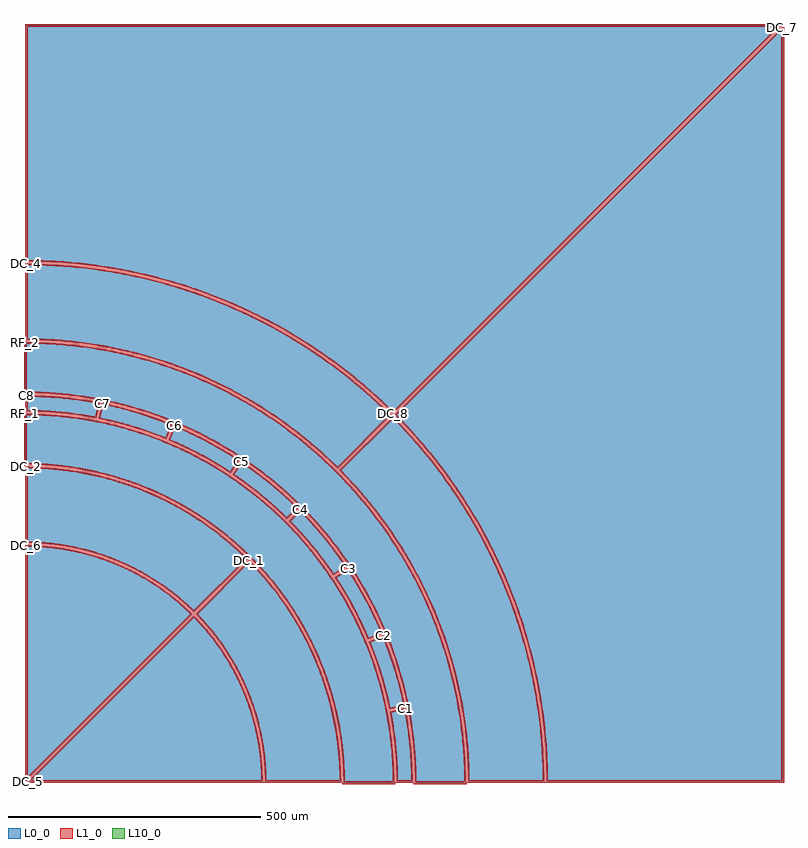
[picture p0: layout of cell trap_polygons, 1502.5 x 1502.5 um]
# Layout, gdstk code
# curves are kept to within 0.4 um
import gdstk
lib = gdstk.Library(unit=1e-6, precision=1e-09)
def P(c, l, *ps):  # polygons
    for p in ps: c.add(gdstk.Polygon(p, *l))
L0_0 = (0, 0)
L1_0 = (1, 0)
L10_0 = (10, 0)

trap_polygons = lib.new_cell('trap_polygons')
P(trap_polygons, L0_0, [(727.08,730.616),(691.717,764.181),(654.807,796.036),(609.899,830.945),(569.922,858.856),(528.671,884.846),(486.237,908.856),(442.715,930.833),(390.694,953.836),(345.151,971.245),(298.837,986.48),(251.854,999.508),(204.307,1010.299),(156.303,1018.83),(107.95,1025.082),(51.239,1029.476),(2.5,1030.747),(2.5,1497.5),(1493.964,1497.5)],
  [(1497.5,1493.964),(1497.5,2.5),(1030.747,2.5),(1029.476,51.239),(1025.082,107.95),(1018.83,156.303),(1010.299,204.307),(999.508,251.854),(986.48,298.837),(971.245,345.151),(953.836,390.694),(930.833,442.715),(908.856,486.237),(884.846,528.671),(858.856,569.922),(830.945,609.899),(796.036,654.807),(764.181,691.717),(730.616,727.08)],
  [(2.5,469.243),(28.188,468.403),(50.143,466.563),(71.986,463.695),(93.672,459.806),(115.15,454.902),(136.375,448.996),(160.754,440.856),(181.269,432.825),(201.385,423.839),(221.057,413.92),(240.241,403.088),(261.951,389.329),(279.936,376.605),(297.304,363.051),(314.017,348.696),(330.037,333.573),(2.5,6.036)],
  [(6.036,2.5),(333.573,330.037),(348.696,314.017),(363.051,297.304),(376.605,279.936),(389.329,261.951),(403.088,240.241),(413.92,221.057),(423.839,201.385),(432.825,181.269),(440.856,160.754),(448.996,136.375),(454.902,115.15),(459.806,93.672),(463.695,71.986),(466.563,50.143),(468.403,28.188),(469.243,2.5)],
  [(2.5,1025.747),(51.002,1024.481),(99.389,1020.924),(147.554,1015.082),(203.322,1005.397),(250.636,994.658),(305.121,979.318),(351.088,963.795),(396.27,946.115),(447.855,922.816),(490.991,900.606),(533.029,876.381),(573.874,850.195),(613.435,822.108),(651.623,792.181),(688.354,760.481),(723.545,727.08),(617.478,621.014),(582.322,654.095),(550.775,680.871),(517.998,706.128),(484.065,729.808),(449.051,751.858),(413.035,772.231),(376.096,790.879),(338.318,807.762),(299.785,822.841),(260.583,836.083),(220.798,847.459),(173.766,858.338),(133.028,865.587),(91.992,870.905),(43.864,874.651),(2.5,875.746)],
  [(727.08,723.545),(760.481,688.354),(792.181,651.623),(822.108,613.435),(850.195,573.874),(876.381,533.029),(900.606,490.991),(922.816,447.855),(946.115,396.27),(963.795,351.088),(979.318,305.121),(994.658,250.636),(1005.397,203.322),(1015.082,147.554),(1020.924,99.389),(1024.481,51.002),(1025.747,2.5),(875.746,2.5),(874.651,43.864),(870.905,91.992),(865.587,133.028),(858.338,173.766),(847.459,220.798),(836.083,260.583),(822.841,299.785),(807.762,338.318),(790.879,376.096),(772.231,413.035),(751.858,449.051),(729.808,484.065),(706.128,517.998),(680.871,550.775),(654.095,582.322),(621.014,617.478)],
  [(2.5,624.245),(31.897,623.435),(61.224,621.24),(90.414,617.668),(119.404,612.724),(148.129,606.42),(176.526,598.771),(209.155,588.169),(236.624,577.665),(263.568,565.88),(294.259,550.545),(319.861,536.075),(344.754,520.416),(368.881,503.602),(392.19,485.67),(418.28,463.39),(439.64,443.176),(333.573,337.108),(317.38,352.396),(297.607,369.247),(279.945,382.811),(261.665,395.53),(239.614,409.266),(220.137,420.063),(200.175,429.934),(179.772,438.857),(158.972,446.812),(137.822,453.782),(116.367,459.752),(94.657,464.708),(69.067,469.194),(46.965,471.919),(24.76,473.603),(2.5,474.243)],
  [(443.176,439.64),(463.39,418.28),(485.67,392.19),(503.602,368.881),(520.416,344.754),(536.075,319.861),(550.545,294.259),(565.88,263.568),(577.665,236.624),(588.169,209.155),(598.771,176.526),(606.42,148.129),(612.724,119.404),(617.668,90.414),(621.24,61.224),(623.435,31.897),(624.245,2.5),(474.243,2.5),(473.603,24.76),(471.919,46.965),(469.194,69.067),(464.708,94.657),(459.752,116.367),(453.782,137.822),(446.812,158.972),(438.857,179.772),(429.934,200.175),(420.063,220.137),(409.266,239.614),(395.53,261.665),(382.811,279.945),(369.247,297.607),(352.396,317.38),(337.108,333.573)],
  [(2.5,765.746),(38.822,764.765),(75.057,762.063),(111.122,757.644),(146.938,751.52),(140.792,720.625),(106.5,726.485),(71.969,730.714),(37.276,733.303),(2.5,734.246)],
  [(151.842,750.545),(187.274,742.497),(222.285,732.777),(256.796,721.408),(290.729,708.414),(278.674,679.311),(246.184,691.749),(213.142,702.633),(179.62,711.941),(145.696,719.65)],
  [(295.348,706.5),(328.53,691.694),(360.972,675.331),(392.601,657.447),(423.347,638.083),(405.846,611.892),(376.407,630.429),(346.123,647.551),(315.062,663.219),(283.293,677.398)],
  [(427.504,635.306),(457.16,614.311),(485.787,591.933),(513.319,568.222),(539.696,543.232),(517.422,520.958),(492.165,544.882),(465.803,567.583),(438.396,589.01),(410.004,609.114)],
  [(543.232,539.696),(568.222,513.319),(591.933,485.787),(614.311,457.16),(635.306,427.504),(609.114,410.004),(589.01,438.396),(567.583,465.803),(544.882,492.165),(520.958,517.422)],
  [(638.083,423.347),(657.447,392.601),(675.331,360.972),(691.694,328.53),(706.5,295.348),(677.398,283.293),(663.219,315.062),(647.551,346.123),(630.429,376.407),(611.892,405.846)],
  [(708.414,290.729),(721.408,256.796),(732.777,222.285),(742.497,187.274),(750.545,151.842),(719.65,145.696),(711.941,179.62),(702.633,213.142),(691.749,246.184),(679.311,278.674)],
  [(751.52,146.938),(757.644,111.122),(762.063,75.057),(764.765,38.822),(765.746,2.5),(734.246,2.5),(733.303,37.276),(730.714,71.969),(726.485,106.5),(720.625,140.792)],
  [(0,870.75),(41.018,869.783),(81.945,866.886),(129.457,861.073),(169.875,854.019),(209.916,845.069),(256.036,832.257),(294.956,819.272),(333.222,804.468),(370.747,787.878),(407.45,769.539),(449.121,745.987),(483.763,724.002),(517.331,700.41),(549.75,675.263),(586.026,644.034),(615.713,615.713),(644.034,586.026),(675.263,549.75),(700.41,517.331),(724.002,483.763),(745.987,449.121),(769.539,407.45),(787.878,370.747),(804.468,333.222),(819.272,294.956),(832.257,256.036),(845.069,209.916),(854.019,169.875),(861.073,129.457),(866.886,81.945),(869.783,41.018),(870.75,0),(770.75,0),(769.894,36.307),(766.736,78.558),(762.184,114.589),(755.94,150.366),(748.018,185.809),(738.435,220.839),(727.212,255.379),(712.08,294.953),(694.797,333.637),(678.309,365.996),(660.315,397.542),(640.855,428.206),(619.973,457.919),(593.873,491.295),(570.071,518.724),(545.003,545.003),(518.724,570.071),(491.295,593.873),(457.919,619.973),(428.206,640.855),(397.542,660.315),(365.996,678.309),(333.637,694.797),(294.953,712.08),(255.379,727.212),(220.839,738.435),(185.809,748.018),(150.366,755.94),(114.589,762.184),(78.558,766.736),(36.307,769.894),(0,770.75)],
  [(0,729.25),(34.352,728.44),(68.628,726.014),(102.752,721.975),(142.27,715.238),(175.804,707.742),(208.948,698.675),(247.025,686.137),(279.072,673.739),(310.5,659.845),(341.238,644.486),(376.137,624.761),(405.15,606.349),(433.263,586.591),(464.841,561.897),(490.794,539.376),(515.658,515.658),(539.376,490.794),(561.897,464.841),(586.591,433.263),(606.349,405.15),(624.761,376.137),(644.486,341.238),(659.845,310.5),(673.739,279.072),(686.137,247.025),(698.675,208.948),(707.742,175.804),(715.238,142.27),(721.975,102.752),(726.014,68.628),(728.44,34.352),(729.25,0),(629.25,0),(628.299,34.577),(625.973,64.136),(622.257,93.552),(617.159,122.761),(609.481,156.488),(601.433,185.025),(592.049,213.151),(581.351,240.804),(569.362,267.922),(556.11,294.445),(541.622,320.314),(523.202,349.593),(506.153,373.851),(487.981,397.279),(468.725,419.825),(444.947,444.947),(419.825,468.725),(397.279,487.981),(373.851,506.153),(349.593,523.202),(320.314,541.622),(294.445,556.11),(267.922,569.362),(240.804,581.351),(213.151,592.049),(185.025,601.433),(156.488,609.481),(122.761,617.159),(93.552,622.257),(64.136,625.973),(34.577,628.299),(0,629.25)])
P(trap_polygons, L1_0, [(404.701,950.689),(353.654,970.842),(307.349,986.48),(260.356,999.91),(212.781,1011.103),(164.73,1020.034),(108.211,1027.568),(59.498,1031.536),(5,1033.231),(5,1495),(404.701,1495),(404.701,1500),(0,1500),(0,1028.263),(51.115,1026.979),(99.622,1023.413),(147.906,1017.557),(195.859,1009.424),(251.243,997.083),(305.862,981.706),(351.943,966.144),(404.701,945.259)],
  [(727.081,730.616),(728.848,728.848),(1497.5,1497.5),(1496.464,1500),(404.701,1500),(404.701,1495),(1487.929,1495),(727.069,734.14),(693.395,766.034),(656.395,797.967),(617.926,828.114),(578.075,856.408),(536.93,882.786),(494.584,907.189),(451.131,929.562),(404.701,950.689),(404.701,945.259),(456.228,921.496),(499.293,898.891),(541.242,874.274),(581.979,847.702),(614.936,824.107),(646.937,799.231),(684.008,767.744),(725.324,728.837)],
  [(1500,399.168),(1495,399.168),(1495,5),(1033.231,5),(1031.536,59.498),(1026.683,116.31),(1018.704,172.767),(1009.394,220.746),(995.681,276.09),(986.48,307.349),(976.298,338.302),(965.145,368.918),(953.032,399.168),(947.603,399.168),(966.144,351.943),(981.706,305.862),(997.083,251.243),(1007.849,203.811),(1017.557,147.906),(1023.413,99.622),(1026.979,51.115),(1028.263,0),(1500,0)],
  [(1500,1493.964),(1497.501,1493.964),(1495.732,1495.732),(727.092,727.092),(762.327,690.04),(794.105,653.219),(824.107,614.936),(852.264,575.278),(878.514,534.332),(902.799,492.191),(925.064,448.948),(947.603,399.168),(953.032,399.168),(939.972,429.02),(925.977,458.446),(899.278,508.827),(882.786,536.93),(865.417,564.499),(832.96,611.378),(803.117,650.083),(771.478,687.334),(734.14,727.069),(1495,1487.929),(1495,399.168),(1500,399.168)],
  [(333.573,333.573),(312.937,353.014),(293.139,369.618),(272.462,385.114),(250.967,399.454),(222.234,416.125),(189.023,432.225),(186.566,433.288),(173.543,433.288),(197.007,423.136),(216.65,413.423),(235.816,402.798),(254.462,391.286),(272.548,378.911),(292.885,363.42),(309.62,349.272),(326.485,333.556),(5,12.071),(5,433.288),(0,433.288),(0,3.536),(2.5,2.5)],
  [(185.634,433.691),(161.61,443.204),(137.101,451.388),(112.181,458.218),(86.924,463.673),(57.745,468.203),(32.023,470.662),(2.523,471.743),(2.5,469.243),(0,469.243),(0,433.288),(5,433.288),(5,466.72),(42.606,464.801),(60.756,462.779),(82.41,459.417),(103.883,455.043),(128.642,448.672),(149.56,442.14),(173.543,433.288),(186.566,433.288)],
  [(334.355,325.672),(349.272,309.62),(365.701,290.032),(378.911,272.548),(391.286,254.462),(402.798,235.816),(413.423,216.65),(423.136,197.007),(432.225,176.166),(432.225,189.023),(416.125,222.234),(399.454,250.967),(385.114,272.462),(369.618,293.139),(353.014,312.937),(333.573,333.573),(4.268,4.268),(6.036,2.499),(6.036,0),(432.225,0),(432.225,5),(12.071,5),(333.556,326.485)],
  [(471.766,0.023),(471.105,24.653),(469.049,50.41),(466.166,72.37),(461.504,97.785),(456.406,119.339),(449.187,144.149),(440.621,168.527),(432.225,189.023),(432.225,176.166),(440.956,153.015),(447.652,132.149),(454.216,107.441),(458.758,86.003),(462.289,64.376),(464.454,46.242),(466.112,24.391),(466.72,5),(432.225,5),(432.225,0)],
  [(242.195,844.192),(214.728,851.595),(187.799,857.936),(160.683,863.426),(126.567,869.082),(99.13,872.638),(64.7,875.864),(37.08,877.467),(5,878.23),(5,1023.231),(34.757,1022.66),(66.985,1021.055),(123.205,1015.806),(179.05,1007.463),(210.727,1001.316),(242.195,994.174),(242.195,999.315),(203.817,1007.848),(171.937,1013.773),(139.887,1018.69),(107.697,1022.595),(67.312,1026.044),(26.823,1027.9),(2.516,1028.247),(2.5,1025.747),(0,1025.747),(0,873.263),(50.606,871.782),(78.04,869.756),(105.396,866.866),(139.441,862.045),(173.27,855.887),(206.831,848.402),(242.195,838.985)],
  [(473.859,912.546),(448.947,925.065),(419.555,938.761),(389.746,951.523),(359.55,963.339),(328.996,974.197),(298.115,984.086),(266.938,992.997),(242.195,999.315),(242.195,994.174),(281.187,983.857),(312.07,974.501),(350.232,961.446),(380.374,949.924),(424.867,930.875),(473.859,906.91)],
  [(473.859,739.446),(450.333,754.005),(420.3,771.149),(389.616,787.098),(364.631,798.979),(332.894,812.714),(307.13,822.796),(274.5,834.25),(242.195,844.192),(242.195,838.985),(279.462,827.325),(311.816,815.682),(343.686,802.774),(375.023,788.621),(399.676,776.418),(423.933,763.444),(447.769,749.712),(473.859,733.493)],
  [(727.08,727.08),(701.966,751.36),(671.81,778.441),(640.609,804.312),(608.413,828.934),(575.272,852.267),(541.237,874.277),(506.362,894.928),(473.859,912.546),(473.859,906.91),(510.905,886.576),(545.448,865.752),(585.777,838.991),(618.386,815.254),(643.785,795.35),(668.543,774.655),(692.636,753.19),(719.998,727.069),(617.467,624.538),(583.984,655.962),(546.952,687.144),(508.258,716.238),(473.859,739.446),(473.859,733.493),(510.958,708.158),(549.202,678.927),(585.778,647.634),(617.49,617.49)],
  [(1028.263,0.016),(1027.9,26.823),(1026.543,59.221),(1024.165,91.559),(1020.769,123.807),(1012.386,179.925),(1006.209,211.757),(999.032,243.378),(993.881,243.378),(999.624,218.615),(1006.02,186.987),(1011.416,155.173),(1015.806,123.205),(1021.055,66.985),(1022.66,34.757),(1023.231,5),(878.23,5),(877.148,43.989),(874.736,78.487),(870.968,112.863),(865.85,147.064),(856.431,194.55),(844.41,241.445),(843.849,243.378),(838.642,243.378),(846.747,213.506),(853.052,186.73),(859.742,153.002),(864.134,125.846),(868.419,91.73),(870.877,64.331),(872.735,29.997),(873.263,0)],
  [(842.482,248.088),(829.823,287.606),(817.857,320.052),(804.623,352.001),(790.142,383.405),(767.815,426.36),(743.155,468.02),(738.342,475.568),(732.388,475.568),(746.162,453.66),(760.081,429.932),(773.246,405.779),(785.643,381.222),(802.774,343.686),(815.682,311.816),(827.325,279.462),(838.642,243.378),(843.849,243.378)],
  [(997.082,251.247),(986.406,290.347),(976.76,321.305),(966.144,351.944),(951.523,389.746),(932.029,434.305),(911.657,475.568),(906.022,475.568),(920.567,446.764),(934.196,417.515),(955.804,365.349),(966.848,335.029),(976.932,304.377),(986.043,273.422),(993.881,243.378),(999.032,243.378)],
  [(910.449,477.892),(890.908,513.401),(869.983,548.113),(847.706,581.974),(828.934,608.413),(804.312,640.609),(778.441,671.81),(756.871,696.021),(728.859,725.301),(727.081,723.545),(725.313,725.313),(617.49,617.49),(647.634,585.778),(678.927,549.202),(708.158,510.958),(732.388,475.568),(738.342,475.568),(712.213,513.883),(687.144,546.952),(655.962,583.984),(624.538,617.467),(727.069,719.998),(753.19,692.636),(774.655,668.543),(795.35,643.785),(815.254,618.386),(838.991,585.777),(861.425,552.257),(886.576,510.905),(906.022,475.568),(911.657,475.568)],
  [(138.548,456.174),(106.098,464.794),(73.121,471.109),(39.781,475.087),(5,476.721),(5,621.725),(36.644,620.669),(70.688,617.719),(104.518,612.902),(138.548,606.115),(138.548,611.243),(105.359,617.831),(71.257,622.686),(36.939,625.661),(2.52,626.745),(2.5,624.245),(0,624.245),(0,471.766),(35.683,470.398),(68.703,466.72),(104.985,459.92),(138.548,450.942)],
  [(269.237,565.974),(237.572,579.979),(205.349,592.155),(172.507,602.542),(138.548,611.243),(138.548,606.115),(171.13,597.735),(203.711,587.431),(235.676,575.352),(269.237,560.427)],
  [(269.237,393.449),(237.649,413.296),(204.607,430.612),(170.311,445.292),(138.548,456.174),(138.548,450.942),(171.969,439.289),(205.79,424.498),(238.35,407.108),(269.237,387.374)],
  [(443.176,443.176),(423.595,461.933),(405.137,478.204),(386.055,493.738),(362.373,511.372),(337.886,527.872),(316.906,540.728),(295.437,552.75),(269.237,565.974),(269.237,560.427),(293.08,548.34),(318.58,533.929),(343.373,518.332),(367.404,501.585),(401.905,474.389),(420.216,458.248),(436.09,443.162),(333.557,340.628),(319.053,354.254),(302.071,368.841),(284.424,382.614),(269.237,393.449),(269.237,387.374),(284.395,376.387),(301.751,362.622),(318.441,348.057),(333.589,333.589)],
  [(626.765,0.02),(625.661,36.939),(622.686,71.257),(617.831,105.359),(611.11,139.143),(605.977,139.143),(612.902,104.518),(617.719,70.688),(620.669,36.644),(621.725,5),(476.721,5),(476.1,24.89),(474.406,47.213),(471.667,69.431),(467.888,91.496),(462.175,116.981),(455.991,139.143),(450.759,139.143),(459.92,104.985),(466.72,68.703),(470.398,35.683),(471.766,0)],
  [(455.076,142.114),(447.903,163.32),(439.742,184.167),(430.612,204.607),(420.532,224.596),(407.602,247.287),(393.301,269.452),(387.226,269.452),(407.108,238.35),(424.498,205.79),(439.289,171.969),(450.759,139.143),(455.991,139.143)],
  [(609.998,143.937),(598.312,186.652),(583.638,228.434),(565.87,269.452),(560.324,269.452),(575.352,235.676),(587.431,203.711),(597.735,171.13),(605.977,139.143),(611.11,139.143)],
  [(563.92,273.513),(552.75,295.437),(540.728,316.906),(527.872,337.886),(511.372,362.373),(496.754,382.166),(481.371,401.37),(465.245,419.955),(444.957,441.394),(443.176,439.64),(441.408,441.408),(333.589,333.589),(348.057,318.441),(362.622,301.751),(374.15,287.333),(387.226,269.452),(393.301,269.452),(380.376,287.41),(368.841,302.071),(354.254,319.053),(340.628,333.557),(443.162,436.091),(471.219,405.618),(498.684,371.331),(515.62,347.433),(531.411,322.763),(546.022,297.377),(560.324,269.452),(565.87,269.452)],
  [(2.518,768.246),(2.482,763.246),(38.695,762.268),(74.812,759.575),(110.759,755.171),(143.994,749.538),(138.824,723.547),(106.863,728.959),(72.214,733.202),(37.403,735.8),(5,736.727),(5,765.746),(0,765.746),(0,731.764),(37.149,730.806),(71.724,728.226),(106.138,724.012),(142.76,717.703),(149.863,753.505),(111.485,760.118),(75.302,764.551),(38.949,767.262)],
  [(152.347,752.993),(151.336,748.096),(186.663,740.073),(221.56,730.385),(255.958,719.052),(287.455,707.044),(277.314,682.561),(247.022,694.104),(213.867,705.026),(180.232,714.365),(148.632,721.596),(154.294,750.057),(149.39,751.032),(142.76,717.703),(179.009,709.517),(212.416,700.241),(245.346,689.394),(280.034,676.062),(293.985,709.79),(257.635,723.763),(223.011,735.169),(187.886,744.921)],
  [(296.321,708.803),(294.375,704.198),(327.457,689.436),(359.794,673.126),(391.32,655.301),(419.869,637.379),(405.146,615.344),(377.689,632.575),(347.302,649.756),(316.135,665.477),(286.553,678.734),(297.658,705.544),(293.038,707.457),(280.034,676.062),(313.989,660.961),(344.945,645.346),(375.126,628.282),(406.546,608.44),(426.809,638.798),(393.883,659.594),(362.151,677.536),(329.602,693.953)],
  [(428.908,637.374),(426.1,633.237),(455.668,612.305),(484.201,590),(511.644,566.367),(536.148,543.219),(517.409,524.48),(493.841,546.737),(467.389,569.515),(439.888,591.015),(413.461,609.789),(429.583,633.917),(425.426,636.694),(406.546,608.44),(436.903,587.004),(464.217,565.65),(490.49,543.027),(517.435,517.435),(543.232,543.257),(514.995,570.077),(487.373,593.865),(458.653,616.316)],
  [(545.012,541.451),(541.451,537.941),(566.367,511.644),(590,484.201),(612.305,455.668),(631.823,428.184),(609.789,413.461),(591.015,439.888),(569.515,467.389),(546.737,493.841),(524.48,517.409),(545,537.929),(541.464,541.464),(517.435,517.435),(543.027,490.49),(565.65,464.217),(587.004,436.903),(608.44,406.546),(638.778,426.84),(616.316,458.653),(593.865,487.373),(570.077,514.995)],
  [(640.172,424.721),(635.995,421.973),(655.301,391.32),(673.126,359.794),(689.436,327.457),(703.217,296.694),(678.734,286.553),(665.477,316.135),(649.756,347.302),(632.575,377.689),(615.344,405.146),(639.472,421.268),(636.694,425.426),(608.44,406.546),(628.282,375.126),(645.346,344.945),(660.961,313.989),(676.062,280.034),(709.776,294.019),(693.953,329.602),(677.536,362.151),(659.594,393.883)],
  [(710.73,291.669),(706.097,289.789),(719.052,255.958),(730.385,221.56),(740.073,186.663),(747.587,153.802),(721.596,148.632),(714.365,180.232),(705.026,213.867),(694.104,247.022),(682.561,277.314),(709.37,288.419),(707.457,293.038),(676.062,280.034),(689.394,245.346),(700.241,212.416),(709.517,179.009),(717.703,142.76),(753.498,149.899),(744.921,187.886),(735.169,223.011),(723.763,257.635)],
  [(753.975,147.408),(749.065,146.468),(755.171,110.759),(759.575,74.812),(762.268,38.695),(763.228,5),(736.727,5),(735.8,37.403),(733.202,72.214),(728.959,106.863),(723.547,138.824),(752.008,144.486),(751.032,149.39),(717.703,142.76),(724.012,106.138),(728.226,71.724),(730.806,37.149),(731.764,0),(768.264,0.018),(767.262,38.949),(764.551,75.302),(760.118,111.485)],
  [(248.85,732.108),(215.73,742.547),(186.411,750.444),(156.805,757.184),(126.957,762.756),(96.914,767.153),(66.721,770.366),(36.425,772.392),(2.5,773.24),(2.5,868.24),(54.518,866.537),(81.71,864.397),(108.821,861.404),(149.277,855.321),(182.742,848.801),(215.925,840.972),(248.85,831.824),(248.85,837.037),(217.168,845.815),(183.794,853.689),(150.137,860.247),(116.248,865.478),(82.18,869.375),(41.136,872.281),(0.01,873.25),(0,870.75),(-2.5,870.75),(-2.5,768.26),(24.131,767.871),(54.259,766.332),(78.303,764.249),(108.247,760.586),(143.956,754.642),(179.344,747.023),(214.335,737.746),(248.85,726.83)],
  [(479.434,729.869),(450.41,748.129),(426.689,761.907),(396.447,778.071),(365.595,793.036),(334.178,806.778),(308.672,816.877),(276.364,828.365),(248.85,837.037),(248.85,831.824),(281.241,821.439),(313.274,809.764),(351.071,794.108),(381.977,779.712),(406.28,767.329),(430.182,754.189),(453.659,740.305),(479.434,723.871)],
  [(479.434,606.674),(454.505,625.572),(424.532,646.288),(393.616,665.569),(367.183,680.509),(340.183,694.4),(307.095,709.654),(278.997,721.163),(248.85,732.108),(248.85,726.83),(277.193,716.5),(305.109,705.065),(337.983,689.91),(364.808,676.109),(396.253,658.173),(421.787,642.109),(451.566,621.527),(479.434,600.288)],
  [(659.55,572.328),(641.247,592.763),(622.312,612.612),(597.781,636.572),(577.491,655.035),(556.631,672.851),(529.785,694.185),(507.719,710.484),(479.434,729.869),(479.434,723.871),(510.345,702.429),(537.528,681.851),(563.883,660.222),(589.369,637.576),(623.513,604.226),(642.185,584.343),(659.55,564.664)],
  [(659.55,403.617),(642.934,429.595),(621.983,459.404),(599.652,488.194),(580.023,511.359),(555.291,538.115),(533.737,559.5),(506.788,584.022),(479.434,606.674),(479.434,600.288),(503.511,580.245),(530.286,555.882),(551.701,534.635),(576.273,508.053),(599.566,480.343),(621.527,451.566),(642.109,421.787),(659.55,393.945)],
  [(764.84,421.403),(740.962,462.106),(714.449,502.123),(685.778,540.624),(659.55,572.328),(659.55,564.664),(690.21,526.752),(718.113,488.029),(743.845,447.831),(764.84,410.937)],
  [(764.84,113.71),(758.392,150.854),(750.444,186.411),(739.067,227.367),(727.536,261.929),(712.044,301.512),(697.05,334.719),(680.509,367.183),(659.55,403.617),(659.55,393.945),(681.755,354.144),(700.186,316.146),(718.655,271.557),(732.491,231.657),(742.591,196.894),(752.288,155.791),(759.712,114.218),(764.84,72.299)],
  [(873.26,-2.49),(872.819,27.429),(871.527,54.832),(869.375,82.18),(866.364,109.447),(862.499,136.606),(857.782,163.631),(852.219,190.494),(845.815,217.168),(838.576,243.629),(830.51,269.849),(821.624,295.803),(811.927,321.465),(801.429,346.809),(790.14,371.812),(778.071,396.447),(764.84,421.403),(764.84,410.937),(779.712,381.977),(791.326,357.297),(804.743,325.955),(814.585,300.516),(829.867,255.301),(842.642,209.313),(852.871,162.694),(857.56,135.824),(861.404,108.821),(864.397,81.71),(866.537,54.518),(868.223,6.819),(868.24,2.5),(773.24,2.5),(772.654,30.358),(770.866,60.668),(768.58,84.852),(764.84,113.71),(764.84,72.299),(767.397,36.19),(768.26,-2.5)],
  [(204.635,597.689),(181.012,605.263),(157.11,611.902),(132.966,617.599),(103.725,623.177),(79.179,626.768),(54.511,629.394),(29.76,631.049),(2.5,631.74),(2.5,726.74),(28.532,726.19),(51.328,724.935),(74.074,722.965),(102.4,719.5),(130.568,714.925),(152.96,710.471),(180.735,703.918),(204.635,697.339),(204.635,702.553),(176.407,710.168),(148.39,716.546),(120.144,721.82),(91.713,725.98),(57.412,729.494),(22.985,731.389),(0.01,731.75),(0,729.25),(-2.5,729.25),(-2.5,626.76),(19.687,626.441),(44.265,625.185),(88.31,620.497),(117.441,615.649),(146.312,609.433),(174.858,601.864),(204.635,592.397)],
  [(395.7,615.527),(372.491,629.848),(347.476,643.986),(327.077,654.583),(301.126,666.919),(280.029,676.049),(253.271,686.522),(231.582,694.138),(204.635,702.553),(204.635,697.339),(235.407,687.568),(262.219,677.795),(293.857,664.691),(319.726,652.642),(360.075,631.278),(395.7,609.573)],
  [(395.7,492.469),(375.336,508.164),(350.982,525.281),(325.848,541.231),(304.348,553.607),(282.379,565.129),(255.444,577.803),(227.942,589.195),(204.635,597.689),(204.635,592.397),(235.292,580.907),(262.395,569.179),(288.916,556.186),(314.795,541.959),(335.829,529.183),(356.346,515.59),(376.313,501.202),(395.7,486.042)],
  [(544.415,488.943),(525.489,509.234),(509.234,525.489),(475.234,556.427),(453.022,574.656),(434.748,588.602),(395.7,615.527),(395.7,609.573),(417.885,594.59),(440.906,577.726),(463.248,559.97),(484.875,541.352),(513.89,513.89),(544.415,481.427)],
  [(544.415,320.493),(530.729,342.687),(513.997,367.308),(496.124,391.113),(477.149,414.049),(460.526,432.463),(439.643,453.676),(417.784,473.883),(395.7,492.469),(395.7,486.042),(421.811,463.564),(443.179,443.179),(463.564,421.811),(486.042,395.7),(501.202,376.313),(518.373,352.286),(531.804,331.663),(544.415,310.529)],
  [(626.441,378.187),(608.428,406.539),(588.602,434.748),(567.469,461.992),(544.415,488.943),(544.415,481.427),(567.178,454.395),(587.953,427.173),(607.423,399.002),(626.441,368.415)],
  [(626.441,81.689),(621.471,113.501),(615.434,142.65),(606.666,176.253),(597.689,204.635),(585.542,237.169),(573.719,264.488),(560.623,291.221),(544.415,320.493),(544.415,310.529),(562.839,275.732),(579.041,239.847),(592.959,203.015),(604.536,165.382),(612.711,131.913),(619.785,93.18),(624.412,54.08),(626.441,19.687)],
  [(731.76,-2.49),(730.306,45.947),(727.939,74.583),(725.237,97.412),(717.69,142.757),(711.532,170.824),(705.815,193.089),(699.402,215.164),(690.415,242.457),(682.459,264.023),(671.567,290.613),(659.64,316.755),(649.365,337.318),(626.441,378.187),(626.441,368.415),(639.586,345.102),(652.642,319.726),(664.691,293.857),(675.715,267.535),(689.395,230),(702.477,186.258),(712.786,141.782),(720.282,96.746),(724.935,51.328),(726.19,28.532),(726.74,2.5),(631.74,2.5),(630.172,44.619),(626.441,81.689),(626.76,-2.5)])
P(trap_polygons, L10_0, [(0,0),(0,0),(0,0),(0,0)])
trap_polygons.add(gdstk.Label('DC_8', (727.08,730.616), layer=2, texttype=0))
trap_polygons.add(gdstk.Label('DC_7', (1497.5,1493.964), layer=2, texttype=0))
trap_polygons.add(gdstk.Label('DC_6', (2.5,469.243), layer=2, texttype=0))
trap_polygons.add(gdstk.Label('DC_5', (6.036,2.5), layer=2, texttype=0))
trap_polygons.add(gdstk.Label('DC_4', (2.5,1025.747), layer=2, texttype=0))
trap_polygons.add(gdstk.Label('DC_3', (727.08,723.545), layer=2, texttype=0))
trap_polygons.add(gdstk.Label('DC_2', (2.5,624.245), layer=2, texttype=0))
trap_polygons.add(gdstk.Label('DC_1', (443.176,439.64), layer=2, texttype=0))
trap_polygons.add(gdstk.Label('C8', (2.5,765.746), layer=2, texttype=0))
trap_polygons.add(gdstk.Label('C7', (151.842,750.545), layer=2, texttype=0))
trap_polygons.add(gdstk.Label('C6', (295.348,706.5), layer=2, texttype=0))
trap_polygons.add(gdstk.Label('C5', (427.504,635.306), layer=2, texttype=0))
trap_polygons.add(gdstk.Label('C4', (543.232,539.696), layer=2, texttype=0))
trap_polygons.add(gdstk.Label('C3', (638.083,423.347), layer=2, texttype=0))
trap_polygons.add(gdstk.Label('C2', (708.414,290.729), layer=2, texttype=0))
trap_polygons.add(gdstk.Label('C1', (751.52,146.938), layer=2, texttype=0))
trap_polygons.add(gdstk.Label('RF_2', (0,870.75), layer=2, texttype=0))
trap_polygons.add(gdstk.Label('RF_1', (0,729.25), layer=2, texttype=0))

lib.write_gds('trap_polygons.gds')
